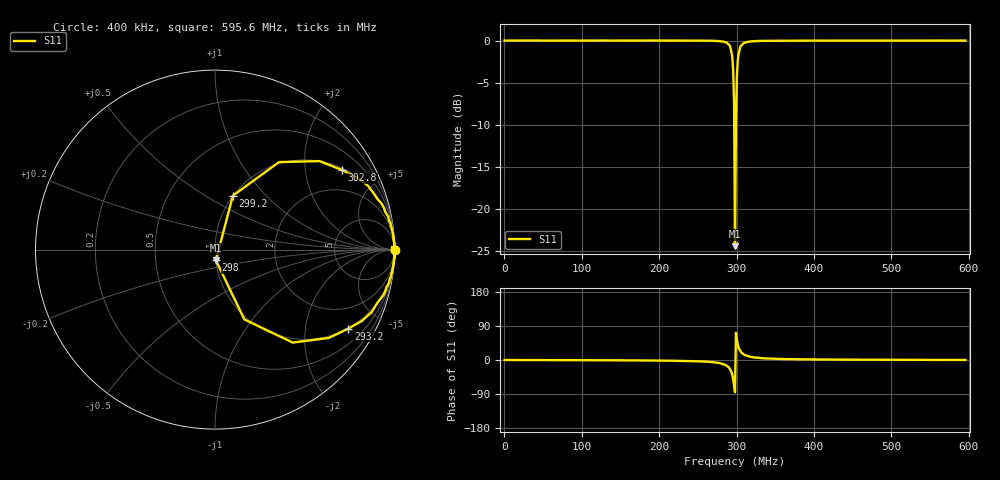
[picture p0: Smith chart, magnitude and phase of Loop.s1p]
! Generated by circuitRF - EM: openEMS
! circuitRF-EM setup: Loop ReferenceGrid
! circuitRF-EM layout: Loop.c3d
! circuitRF-EM written: 2026-10-18 18:18:31Z
! circuitRF-EM geometry: 499d840b778e76c3
! circuitRF-EM mesh: 1773110ca9d2a47e
! circuitRF-EM ports: e37d78baeb0ef280
! circuitRF-EM model: openEMS 0.37.0 (v0.37.0, CSXCAD v0.7.0)
! circuitRF-EM port 1: 'port/1' from 'bottomLeft' to 'bottomRight', lumped, 2.5 Ohm
! circuitRF-EM 3D grid: 154 x 122 x 162 = 3043656 cells; smallest cell 1.6667 mm on y, set by 'OpenEms.GridLines' given line at y = -28.3333 mm
! circuitRF-EM 3D openEMS run port 1: dt 3.38654E-12 s (estimate 3.378E-12 s), 72468 steps, port signals 36.1 dB and energy 41 dB against 40 dB, stopped by openEMS's energy criterion, converged
! circuitRF-EM 3D dielectric loss fitted at: 0.298 GHz
! circuitRF-EM 3D perfect conductors: bottomLeft, topLeft, bottomRight, topRight, leftLower, leftUpper, rightLower, rightUpper
! circuitRF-EM 3D operating temperature: 20 C
! circuitRF-EM: re-running the EM setup rewrites this file. If circuitRF reports it as stale, the layout's cross-section changed after this file was written.
# MHz S RI R 2.5
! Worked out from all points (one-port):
!   497 points, 400 kHz to 595.6 MHz, reference 2.5 ohm
!   lowest |S11| = -24.4 dB at 298 MHz (marker M1), VSWR 1.13, Z = 2.51 - j0.301 ohm
!   |S11| at or under -10 dB: 297 MHz to 299.2 MHz (2.222 MHz wide, 0.745 % of centre)
!   S11 on the Smith chart (normalised r, x): 400 kHz: open; 293.2 MHz: 0.98, -3.38; 298 MHz: 1.00, -0.12; 299.2 MHz: 1.00, +0.67; 302.8 MHz: 1.07, +3.15; 595.6 MHz: open
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0.4  1.001 -0.000693
74.8  1.001 -0.00648
149.2  1 -0.0152
223.6  0.9992 -0.0368
263.2  0.9935 -0.0836
275.2  0.9859 -0.1273
283.6  0.9635 -0.1969
289.6  0.8991 -0.3054
292  0.8177 -0.3979
293.2  0.7422 -0.4402
294.4  0.6338 -0.4922
295.6  0.4334 -0.518
296.8  0.1635 -0.3892
298  0.00512 -0.0597
299.2  0.0997 0.3005
300.4  0.3566 0.4875
301.6  0.582 0.4931
302.8  0.709 0.443
304  0.7895 0.4018
306.4  0.8857 0.311
308.8  0.9265 0.2585
312.4  0.9551 0.1988
320.8  0.981 0.1281
330.4  0.9916 0.0895
372.4  0.9982 0.0373
446.8  0.9995 0.016
521.2  0.9998 0.00782
595.6  0.9998 0.00308
